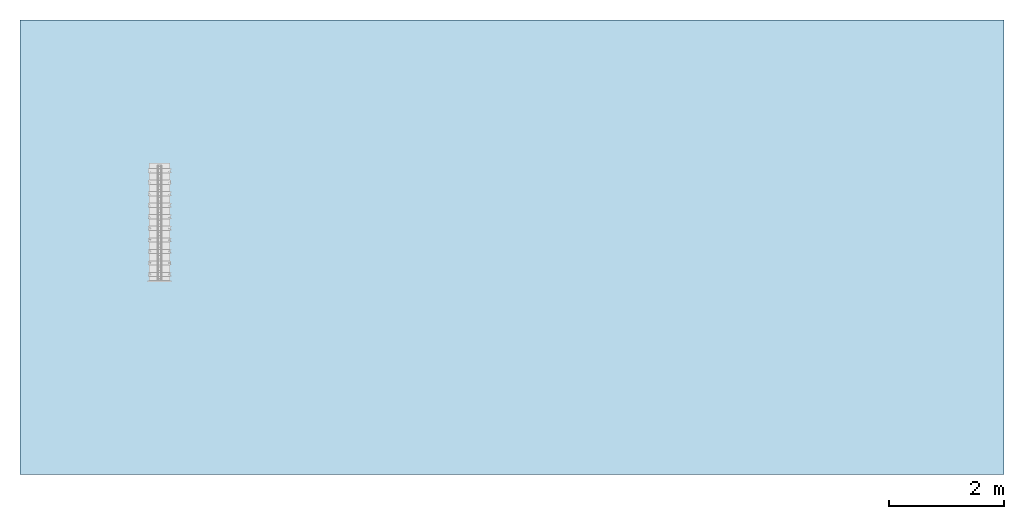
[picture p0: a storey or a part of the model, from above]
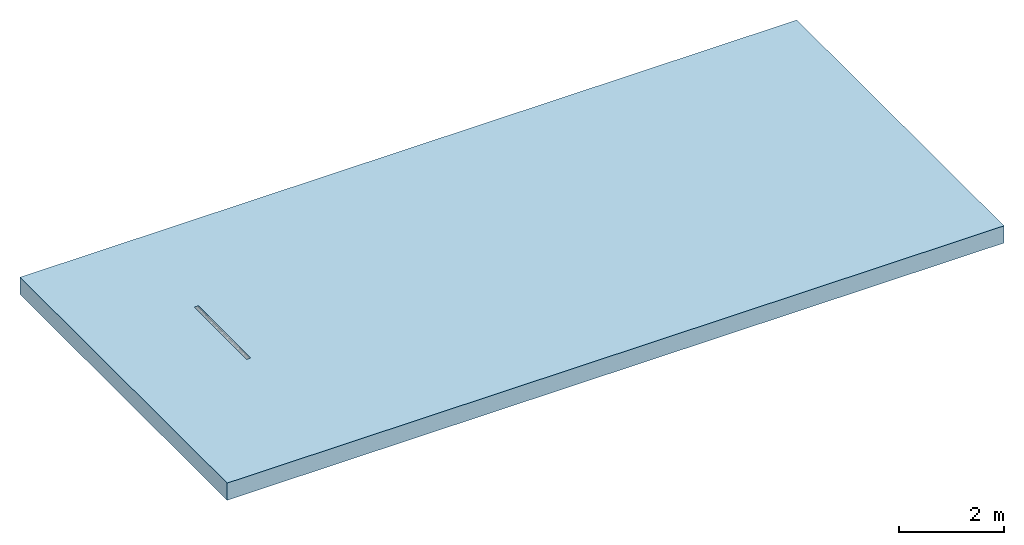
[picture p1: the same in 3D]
Properties of the parts of a building model (IFC2X3)

# File
Description: ViewDefinition [CoordinationView]
File name: 32812 - Q-Flow Edge - G.S.ifc
Time: 2013-07-12T11:20:32
Written by: Autodesk Revit 2013
Made in: 20120221_2030(x64)

# IfcProject, Project Number
LongName: Project Name; Phase: Project Status

# IfcSite, Default
RefLatitude: 42, 21, 30, 344238; RefLongitude: -71, -3, -35, -194702; RefElevation: 0 mm

# IfcBuilding
Pset_BuildingCommon - NumberOfStoreys: 1
Other - Project Issue Date: Issue Date; Project Number: Project Number; Project Name: Project Name; Project Address: ## Street City, State Zip; Client Name: Owner; Project Status: Project Status

# IfcBuildingStorey, Level 1
LongName: Level 1; Elevation: 0 mm
Constraints - Elevation Base: 0; Elevation: 0 mm
Graphics - Line Pattern: Center; Color: 0; Symbol at End 2 Default: yes; Line Weight: 1; Symbol at End 1 Default: no; Symbol: M_Level Head - Circle: M_Level Head - Circle
Dimensions - Computation Height: 0 mm
Identity Data - Structural: no; Name: Level 1; Building Story: yes

# IfcFlowTerminal: 32812 - Q-Flow Edge - G.S, Qmax 350:32812 - Q-Flow Edge - G.S:32812 - Q-Flow Edge - G.S:562865
In: Level 1
Constraints - Level: Level: Level 1; Moves With Nearby Elements: no
Construction - 42351_350 End Cap (Male end): no; 42351_350 End Cap (Female end): no; 32880_225-350 Step Connector: no; E2-QGuard-DuctileIron: no; V_CoarseE1: yes; E3-QFlow-GalvSteel: yes; E1-QFlow-DuctileIron: no; V_Coarse_E5: no; E4-QGuard-GalvSteel: no; E5-QSlot-GalvSteel: no
Phasing - Phase Created: New Construction
Identity Data - Mark: 40; Price: POA - contact ACO; Product Brochure: http://www.aco.co.uk/download.php?id=220; Manufacturer: ACO Technologies plc - ACO Water Management Division; Cost: 0; Telephone: +44 (0)1462 816666; Model: ACO Qmax 350; Model Description: High capacity slot drainage channel system; Maintenance Guidelines: http://www.aco.co.uk/download.php?id=220; OmniClass Title: Rainwater Removal; Assembly Description: Rain Water Drainage; e-mail Sales: customersupport@aco.co.uk; e-mail Technical: technical@aco.co.uk; Installation Guidelines: http://www.aco.co.uk/download.php?id=220; OmniClass Number: 23.70.50.24; Fax: +44 (0)1462 815895; URL: www.aco.co.uk; Product Page URL: http://www.aco.co.uk/product_detail.php?id=79; Address: ACO Business Park, Hitchin Road, Shefford, Bedfordshire, United Kingdom SG17 5TE; Product Code: 32812; Assembly Code: D2040; Type Comments: ACO Qmax 350 channel assembly complete with ACO Q-Flow galvanised steel edge rail
Materials and Finishes - Channel Material: Medium Density Polyethylene; Channel Colour: Black; Edge Rail Finish: Galvanised; Edge Rail Material: Steel; Seal Material: Chloroprene; Seal Colour: Black; Edge Rail Colour: Silver Silver
Dimensions - Depth Overall: 600 mm; BoreCentre: 370 mm; Width Overall: 415 mm; Length: 2000 mm; Floor Opening Width: 90 mm
Model Properties - Multi-Functional End Cap - Channel Recycled Material Content: Variable %; Multi-Functional End Cap - Channel Colour: Black; Multi-Functional End Cap - Seal Recycled Material Content: 0%; Multi-Functional End Cap - Seal Material: Chloroprene; 225-350 Step Connector - Recyclable: Fully recyclable; Multi-Functional End Cap - Model Description: High capacity slot drainage channel system; Multi-Functional End Cap - Dimensions: Ø435mm x 260mm (ØxL); 225-350 Step Connector - Model Description: High capacity slot drainage channel system; Multi-Functional End Cap - Channel Recyclable: Fully recyclable; Multi-Functional End Cap - Channel Material: Medium Density Polyethylene; Multi-Functional End Cap - Seal Colour: Black; Multi-Functional End Cap - Weight: 2.6 kg; Multi-Functional End Cap - Seal Recyclable: Fully recyclable; 225-350 Step Connector - Recycled Material Content: 0%; 225-350 Step Connector - Weight: 0.8 kg; Multi-Functional End Cap - Product Code: 42351; 225-350 Step Connector - Dimensions: Ø435mm x 25mm (ØxL); 225-350 Step Connector - Product Code: 32880; 225-350 Step Connector- Colour: Black; 225-350 Step Connector - Material: High Density Polyethylene
General - SerialNumber: 0; TagNumber: 0
Data - ACO Hydraulic Design Software: http://www.acodesign.co.uk; Drainage Slot Intake Area: 18106mm²/m; Hydraulic Performance: http://www.aco.co.uk/download.php?id=220; Product Weight: 24 kg; Product Standard: BS EN 1433:2002 CE marked; Channel C.S.A: 96211mm²; Load Class: A 15 - F 900; Concrete Surround Volume - Load Class A 15 - E 600: 0.34 m³/m; Installation - Concrete Grade: Refer to brochure; Invert Depth: 550mm; Product Dimensions: 2000mm x 415mm x 600mm (LxWxH); Drainage Slot Width: 26mm; Installation - Reinforcement Details: Refer to brochure; Concrete Surround Volume - Load Class F 900: 0.45 m³/m
Green Building Properties - Channel Recycled Material Content: Variable %; Seal Recycled Material Content: 0%; Channel Recyclable: Fully recyclable; Seal Recyclable: Fully recyclable; Edge Rail Recyclable: Fully recyclable; Edge Rail Recycled Material Content: Between 40% - 90%
Other - Revision: 1; Created by: www.aco.co.uk

# IfcOpeningElement: Opening
In: Level 1
Constraints - Related to Mass: no; Height Offset From Level: 0 mm; Level: Level: Level 1; Room Bounding: yes
Dimensions - Perimeter: 50000 mm; Thickness: 400 mm; Volume: 53723500000 mm3; Area: 134910000 mm2
Structural - Enable Analytical Model: no; Structural: no
Phasing - Phase Created: New Construction
Construction - Default Thickness: 400 mm; Function: 0
Materials and Finishes - Structural Material: Plant
Graphics - Coarse Scale Fill Color: 0
Analytical Properties - Roughness: 1; Absorptance: 0.1

# IfcSlab: Floor:Generic Floor - 400mm, Floor:Generic Floor - 400mm:193825
In: Level 1
PredefinedType: FLOOR; Material: Plant 400 mm
Constraints - Related to Mass: no; Height Offset From Level: 0 mm; Level: Level: Level 1; Room Bounding: yes
Dimensions - Perimeter: 50000 mm; Thickness: 400 mm; Volume: 53723500000 mm3; Area: 134910000 mm2
Structural - Enable Analytical Model: no; Structural: no
Phasing - Phase Created: New Construction
Pset_SlabCommon - Reference: Generic Floor - 400mm; IsExternal: no; LoadBearing: yes
Construction - Default Thickness: 400 mm; Function: 0
Materials and Finishes - Structural Material: Plant
Graphics - Coarse Scale Fill Color: 0
Analytical Properties - Roughness: 1; Absorptance: 0.1
